One B-rep face of a CAD part: STEP entity #71062.
In plain terms, the planar face has unit normal (0, 0, 1).
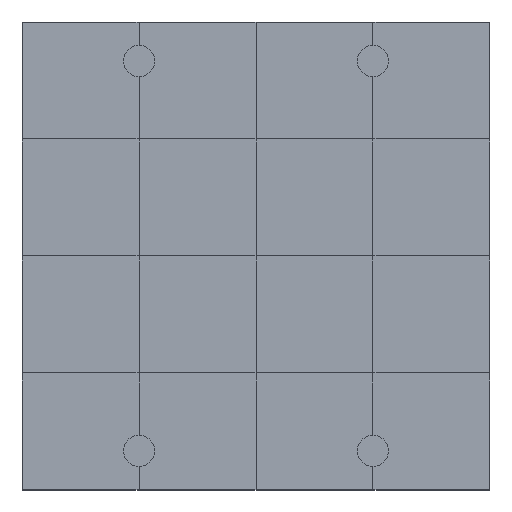
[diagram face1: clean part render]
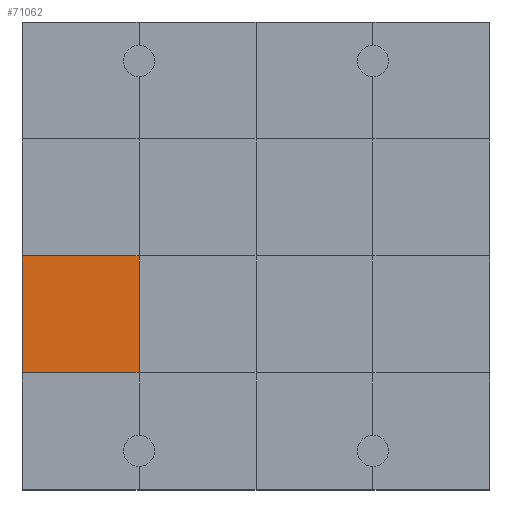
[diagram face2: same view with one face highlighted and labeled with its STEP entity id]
Its self-contained STEP definition (entity closure, numbers rounded to 3 decimals):
#70612 = VERTEX_POINT('',#70613);
#70613 = CARTESIAN_POINT('',(0.,3.,1.2));
#70627 = PLANE('',#70628);
#70628 = AXIS2_PLACEMENT_3D('',#70629,#70630,#70631);
#70629 = CARTESIAN_POINT('',(0.,3.,0.));
#70630 = DIRECTION('',(1.,0.,-0.));
#70631 = DIRECTION('',(0.,0.,1.));
#70653 = PLANE('',#70654);
#70654 = AXIS2_PLACEMENT_3D('',#70655,#70656,#70657);
#70655 = CARTESIAN_POINT('',(0.,0.,1.2));
#70656 = DIRECTION('',(0.,0.,1.));
#70657 = DIRECTION('',(1.,0.,-0.));
#70804 = VERTEX_POINT('',#70805);
#70805 = CARTESIAN_POINT('',(3.,3.,1.2));
#70826 = EDGE_CURVE('',#70612,#70804,#70827,.T.);
#70827 = SURFACE_CURVE('',#70828,(#70832,#70839),.PCURVE_S1.);
#70828 = LINE('',#70829,#70830);
#70829 = CARTESIAN_POINT('',(0.,3.,1.2));
#70830 = VECTOR('',#70831,1.);
#70831 = DIRECTION('',(1.,0.,-0.));
#70832 = PCURVE('',#70653,#70833);
#70833 = DEFINITIONAL_REPRESENTATION('',(#70834),#70838);
#70834 = LINE('',#70835,#70836);
#70835 = CARTESIAN_POINT('',(0.,3.));
#70836 = VECTOR('',#70837,1.);
#70837 = DIRECTION('',(1.,0.));
#70838 = ( GEOMETRIC_REPRESENTATION_CONTEXT(2) 
PARAMETRIC_REPRESENTATION_CONTEXT() REPRESENTATION_CONTEXT('2D SPACE',''
  ) );
#70839 = PCURVE('',#70840,#70845);
#70840 = PLANE('',#70841);
#70841 = AXIS2_PLACEMENT_3D('',#70842,#70843,#70844);
#70842 = CARTESIAN_POINT('',(0.,3.,1.2));
#70843 = DIRECTION('',(0.,0.,1.));
#70844 = DIRECTION('',(1.,0.,-0.));
#70845 = DEFINITIONAL_REPRESENTATION('',(#70846),#70850);
#70846 = LINE('',#70847,#70848);
#70847 = CARTESIAN_POINT('',(0.,0.));
#70848 = VECTOR('',#70849,1.);
#70849 = DIRECTION('',(1.,0.));
#70850 = ( GEOMETRIC_REPRESENTATION_CONTEXT(2) 
PARAMETRIC_REPRESENTATION_CONTEXT() REPRESENTATION_CONTEXT('2D SPACE',''
  ) );
#70885 = VERTEX_POINT('',#70886);
#70886 = CARTESIAN_POINT('',(0.,6.,1.2));
#70912 = EDGE_CURVE('',#70612,#70885,#70913,.T.);
#70913 = SURFACE_CURVE('',#70914,(#70918,#70925),.PCURVE_S1.);
#70914 = LINE('',#70915,#70916);
#70915 = CARTESIAN_POINT('',(0.,3.,1.2));
#70916 = VECTOR('',#70917,1.);
#70917 = DIRECTION('',(-0.,1.,0.));
#70918 = PCURVE('',#70627,#70919);
#70919 = DEFINITIONAL_REPRESENTATION('',(#70920),#70924);
#70920 = LINE('',#70921,#70922);
#70921 = CARTESIAN_POINT('',(1.2,0.));
#70922 = VECTOR('',#70923,1.);
#70923 = DIRECTION('',(0.,-1.));
#70924 = ( GEOMETRIC_REPRESENTATION_CONTEXT(2) 
PARAMETRIC_REPRESENTATION_CONTEXT() REPRESENTATION_CONTEXT('2D SPACE',''
  ) );
#70925 = PCURVE('',#70840,#70926);
#70926 = DEFINITIONAL_REPRESENTATION('',(#70927),#70931);
#70927 = LINE('',#70928,#70929);
#70928 = CARTESIAN_POINT('',(0.,0.));
#70929 = VECTOR('',#70930,1.);
#70930 = DIRECTION('',(0.,1.));
#70931 = ( GEOMETRIC_REPRESENTATION_CONTEXT(2) 
PARAMETRIC_REPRESENTATION_CONTEXT() REPRESENTATION_CONTEXT('2D SPACE',''
  ) );
#71062 = ADVANCED_FACE('',(#71063),#70840,.T.);
#71063 = FACE_BOUND('',#71064,.T.);
#71064 = EDGE_LOOP('',(#71065,#71066,#71067,#71095));
#71065 = ORIENTED_EDGE('',*,*,#70912,.F.);
#71066 = ORIENTED_EDGE('',*,*,#70826,.T.);
#71067 = ORIENTED_EDGE('',*,*,#71068,.T.);
#71068 = EDGE_CURVE('',#70804,#71069,#71071,.T.);
#71069 = VERTEX_POINT('',#71070);
#71070 = CARTESIAN_POINT('',(3.,6.,1.2));
#71071 = SURFACE_CURVE('',#71072,(#71076,#71083),.PCURVE_S1.);
#71072 = LINE('',#71073,#71074);
#71073 = CARTESIAN_POINT('',(3.,3.,1.2));
#71074 = VECTOR('',#71075,1.);
#71075 = DIRECTION('',(-0.,1.,0.));
#71076 = PCURVE('',#70840,#71077);
#71077 = DEFINITIONAL_REPRESENTATION('',(#71078),#71082);
#71078 = LINE('',#71079,#71080);
#71079 = CARTESIAN_POINT('',(3.,0.));
#71080 = VECTOR('',#71081,1.);
#71081 = DIRECTION('',(0.,1.));
#71082 = ( GEOMETRIC_REPRESENTATION_CONTEXT(2) 
PARAMETRIC_REPRESENTATION_CONTEXT() REPRESENTATION_CONTEXT('2D SPACE',''
  ) );
#71083 = PCURVE('',#71084,#71089);
#71084 = PLANE('',#71085);
#71085 = AXIS2_PLACEMENT_3D('',#71086,#71087,#71088);
#71086 = CARTESIAN_POINT('',(3.,3.,1.2));
#71087 = DIRECTION('',(0.,0.,1.));
#71088 = DIRECTION('',(1.,0.,-0.));
#71089 = DEFINITIONAL_REPRESENTATION('',(#71090),#71094);
#71090 = LINE('',#71091,#71092);
#71091 = CARTESIAN_POINT('',(0.,0.));
#71092 = VECTOR('',#71093,1.);
#71093 = DIRECTION('',(0.,1.));
#71094 = ( GEOMETRIC_REPRESENTATION_CONTEXT(2) 
PARAMETRIC_REPRESENTATION_CONTEXT() REPRESENTATION_CONTEXT('2D SPACE',''
  ) );
#71095 = ORIENTED_EDGE('',*,*,#71096,.F.);
#71096 = EDGE_CURVE('',#70885,#71069,#71097,.T.);
#71097 = SURFACE_CURVE('',#71098,(#71102,#71109),.PCURVE_S1.);
#71098 = LINE('',#71099,#71100);
#71099 = CARTESIAN_POINT('',(0.,6.,1.2));
#71100 = VECTOR('',#71101,1.);
#71101 = DIRECTION('',(1.,0.,-0.));
#71102 = PCURVE('',#70840,#71103);
#71103 = DEFINITIONAL_REPRESENTATION('',(#71104),#71108);
#71104 = LINE('',#71105,#71106);
#71105 = CARTESIAN_POINT('',(0.,3.));
#71106 = VECTOR('',#71107,1.);
#71107 = DIRECTION('',(1.,0.));
#71108 = ( GEOMETRIC_REPRESENTATION_CONTEXT(2) 
PARAMETRIC_REPRESENTATION_CONTEXT() REPRESENTATION_CONTEXT('2D SPACE',''
  ) );
#71109 = PCURVE('',#71110,#71115);
#71110 = PLANE('',#71111);
#71111 = AXIS2_PLACEMENT_3D('',#71112,#71113,#71114);
#71112 = CARTESIAN_POINT('',(0.,6.,1.2));
#71113 = DIRECTION('',(0.,0.,1.));
#71114 = DIRECTION('',(1.,0.,-0.));
#71115 = DEFINITIONAL_REPRESENTATION('',(#71116),#71120);
#71116 = LINE('',#71117,#71118);
#71117 = CARTESIAN_POINT('',(0.,0.));
#71118 = VECTOR('',#71119,1.);
#71119 = DIRECTION('',(1.,0.));
#71120 = ( GEOMETRIC_REPRESENTATION_CONTEXT(2) 
PARAMETRIC_REPRESENTATION_CONTEXT() REPRESENTATION_CONTEXT('2D SPACE',''
  ) );
